# Generated deterministically by seda-macro-lef-normalizer-v1; recipe orfs-asap7-fakeram-m4-v1.
VERSION 5.8 ;
BUSBITCHARS "[]" ;
DIVIDERCHAR "/" ;

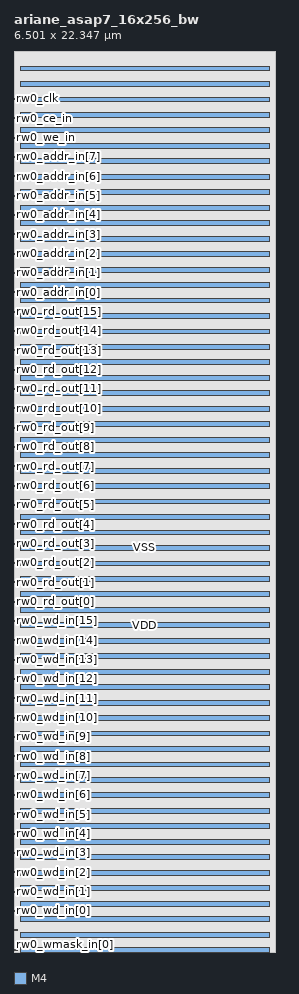
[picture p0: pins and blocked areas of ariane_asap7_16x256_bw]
MACRO ariane_asap7_16x256_bw
  FOREIGN ariane_asap7_16x256_bw 0 0 ;
  CLASS BLOCK ;
  ORIGIN 0 0 ;
  SIZE 6.501 BY 22.347 ;
  SYMMETRY X Y R90 ;
  PIN rw0_wmask_in[0]
    DIRECTION INPUT ;
    USE SIGNAL ;
    SHAPE ABUTMENT ;
    PORT
      LAYER M4 ;
      RECT 0.000 0.048 0.084 0.072 ;
    END
  END rw0_wmask_in[0]
  PIN rw0_wmask_in[1]
    DIRECTION INPUT ;
    USE SIGNAL ;
    SHAPE ABUTMENT ;
    PORT
      LAYER M4 ;
      RECT 0.000 0.528 0.084 0.552 ;
    END
  END rw0_wmask_in[1]
  PIN rw0_wd_in[0]
    DIRECTION INPUT ;
    USE SIGNAL ;
    SHAPE ABUTMENT ;
    PORT
      LAYER M4 ;
      RECT 0.000 1.008 0.084 1.032 ;
    END
  END rw0_wd_in[0]
  PIN rw0_wd_in[1]
    DIRECTION INPUT ;
    USE SIGNAL ;
    SHAPE ABUTMENT ;
    PORT
      LAYER M4 ;
      RECT 0.000 1.488 0.084 1.512 ;
    END
  END rw0_wd_in[1]
  PIN rw0_wd_in[2]
    DIRECTION INPUT ;
    USE SIGNAL ;
    SHAPE ABUTMENT ;
    PORT
      LAYER M4 ;
      RECT 0.000 1.968 0.084 1.992 ;
    END
  END rw0_wd_in[2]
  PIN rw0_wd_in[3]
    DIRECTION INPUT ;
    USE SIGNAL ;
    SHAPE ABUTMENT ;
    PORT
      LAYER M4 ;
      RECT 0.000 2.448 0.084 2.472 ;
    END
  END rw0_wd_in[3]
  PIN rw0_wd_in[4]
    DIRECTION INPUT ;
    USE SIGNAL ;
    SHAPE ABUTMENT ;
    PORT
      LAYER M4 ;
      RECT 0.000 2.928 0.084 2.952 ;
    END
  END rw0_wd_in[4]
  PIN rw0_wd_in[5]
    DIRECTION INPUT ;
    USE SIGNAL ;
    SHAPE ABUTMENT ;
    PORT
      LAYER M4 ;
      RECT 0.000 3.408 0.084 3.432 ;
    END
  END rw0_wd_in[5]
  PIN rw0_wd_in[6]
    DIRECTION INPUT ;
    USE SIGNAL ;
    SHAPE ABUTMENT ;
    PORT
      LAYER M4 ;
      RECT 0.000 3.888 0.084 3.912 ;
    END
  END rw0_wd_in[6]
  PIN rw0_wd_in[7]
    DIRECTION INPUT ;
    USE SIGNAL ;
    SHAPE ABUTMENT ;
    PORT
      LAYER M4 ;
      RECT 0.000 4.368 0.084 4.392 ;
    END
  END rw0_wd_in[7]
  PIN rw0_wd_in[8]
    DIRECTION INPUT ;
    USE SIGNAL ;
    SHAPE ABUTMENT ;
    PORT
      LAYER M4 ;
      RECT 0.000 4.848 0.084 4.872 ;
    END
  END rw0_wd_in[8]
  PIN rw0_wd_in[9]
    DIRECTION INPUT ;
    USE SIGNAL ;
    SHAPE ABUTMENT ;
    PORT
      LAYER M4 ;
      RECT 0.000 5.328 0.084 5.352 ;
    END
  END rw0_wd_in[9]
  PIN rw0_wd_in[10]
    DIRECTION INPUT ;
    USE SIGNAL ;
    SHAPE ABUTMENT ;
    PORT
      LAYER M4 ;
      RECT 0.000 5.808 0.084 5.832 ;
    END
  END rw0_wd_in[10]
  PIN rw0_wd_in[11]
    DIRECTION INPUT ;
    USE SIGNAL ;
    SHAPE ABUTMENT ;
    PORT
      LAYER M4 ;
      RECT 0.000 6.288 0.084 6.312 ;
    END
  END rw0_wd_in[11]
  PIN rw0_wd_in[12]
    DIRECTION INPUT ;
    USE SIGNAL ;
    SHAPE ABUTMENT ;
    PORT
      LAYER M4 ;
      RECT 0.000 6.768 0.084 6.792 ;
    END
  END rw0_wd_in[12]
  PIN rw0_wd_in[13]
    DIRECTION INPUT ;
    USE SIGNAL ;
    SHAPE ABUTMENT ;
    PORT
      LAYER M4 ;
      RECT 0.000 7.248 0.084 7.272 ;
    END
  END rw0_wd_in[13]
  PIN rw0_wd_in[14]
    DIRECTION INPUT ;
    USE SIGNAL ;
    SHAPE ABUTMENT ;
    PORT
      LAYER M4 ;
      RECT 0.000 7.728 0.084 7.752 ;
    END
  END rw0_wd_in[14]
  PIN rw0_wd_in[15]
    DIRECTION INPUT ;
    USE SIGNAL ;
    SHAPE ABUTMENT ;
    PORT
      LAYER M4 ;
      RECT 0.000 8.208 0.084 8.232 ;
    END
  END rw0_wd_in[15]
  PIN rw0_rd_out[0]
    DIRECTION OUTPUT ;
    USE SIGNAL ;
    SHAPE ABUTMENT ;
    PORT
      LAYER M4 ;
      RECT 0.000 8.688 0.084 8.712 ;
    END
  END rw0_rd_out[0]
  PIN rw0_rd_out[1]
    DIRECTION OUTPUT ;
    USE SIGNAL ;
    SHAPE ABUTMENT ;
    PORT
      LAYER M4 ;
      RECT 0.000 9.168 0.084 9.192 ;
    END
  END rw0_rd_out[1]
  PIN rw0_rd_out[2]
    DIRECTION OUTPUT ;
    USE SIGNAL ;
    SHAPE ABUTMENT ;
    PORT
      LAYER M4 ;
      RECT 0.000 9.648 0.084 9.672 ;
    END
  END rw0_rd_out[2]
  PIN rw0_rd_out[3]
    DIRECTION OUTPUT ;
    USE SIGNAL ;
    SHAPE ABUTMENT ;
    PORT
      LAYER M4 ;
      RECT 0.000 10.128 0.084 10.152 ;
    END
  END rw0_rd_out[3]
  PIN rw0_rd_out[4]
    DIRECTION OUTPUT ;
    USE SIGNAL ;
    SHAPE ABUTMENT ;
    PORT
      LAYER M4 ;
      RECT 0.000 10.608 0.084 10.632 ;
    END
  END rw0_rd_out[4]
  PIN rw0_rd_out[5]
    DIRECTION OUTPUT ;
    USE SIGNAL ;
    SHAPE ABUTMENT ;
    PORT
      LAYER M4 ;
      RECT 0.000 11.088 0.084 11.112 ;
    END
  END rw0_rd_out[5]
  PIN rw0_rd_out[6]
    DIRECTION OUTPUT ;
    USE SIGNAL ;
    SHAPE ABUTMENT ;
    PORT
      LAYER M4 ;
      RECT 0.000 11.568 0.084 11.592 ;
    END
  END rw0_rd_out[6]
  PIN rw0_rd_out[7]
    DIRECTION OUTPUT ;
    USE SIGNAL ;
    SHAPE ABUTMENT ;
    PORT
      LAYER M4 ;
      RECT 0.000 12.048 0.084 12.072 ;
    END
  END rw0_rd_out[7]
  PIN rw0_rd_out[8]
    DIRECTION OUTPUT ;
    USE SIGNAL ;
    SHAPE ABUTMENT ;
    PORT
      LAYER M4 ;
      RECT 0.000 12.528 0.084 12.552 ;
    END
  END rw0_rd_out[8]
  PIN rw0_rd_out[9]
    DIRECTION OUTPUT ;
    USE SIGNAL ;
    SHAPE ABUTMENT ;
    PORT
      LAYER M4 ;
      RECT 0.000 13.008 0.084 13.032 ;
    END
  END rw0_rd_out[9]
  PIN rw0_rd_out[10]
    DIRECTION OUTPUT ;
    USE SIGNAL ;
    SHAPE ABUTMENT ;
    PORT
      LAYER M4 ;
      RECT 0.000 13.488 0.084 13.512 ;
    END
  END rw0_rd_out[10]
  PIN rw0_rd_out[11]
    DIRECTION OUTPUT ;
    USE SIGNAL ;
    SHAPE ABUTMENT ;
    PORT
      LAYER M4 ;
      RECT 0.000 13.968 0.084 13.992 ;
    END
  END rw0_rd_out[11]
  PIN rw0_rd_out[12]
    DIRECTION OUTPUT ;
    USE SIGNAL ;
    SHAPE ABUTMENT ;
    PORT
      LAYER M4 ;
      RECT 0.000 14.448 0.084 14.472 ;
    END
  END rw0_rd_out[12]
  PIN rw0_rd_out[13]
    DIRECTION OUTPUT ;
    USE SIGNAL ;
    SHAPE ABUTMENT ;
    PORT
      LAYER M4 ;
      RECT 0.000 14.928 0.084 14.952 ;
    END
  END rw0_rd_out[13]
  PIN rw0_rd_out[14]
    DIRECTION OUTPUT ;
    USE SIGNAL ;
    SHAPE ABUTMENT ;
    PORT
      LAYER M4 ;
      RECT 0.000 15.408 0.084 15.432 ;
    END
  END rw0_rd_out[14]
  PIN rw0_rd_out[15]
    DIRECTION OUTPUT ;
    USE SIGNAL ;
    SHAPE ABUTMENT ;
    PORT
      LAYER M4 ;
      RECT 0.000 15.888 0.084 15.912 ;
    END
  END rw0_rd_out[15]
  PIN rw0_addr_in[0]
    DIRECTION INPUT ;
    USE SIGNAL ;
    SHAPE ABUTMENT ;
    PORT
      LAYER M4 ;
      RECT 0.000 16.368 0.084 16.392 ;
    END
  END rw0_addr_in[0]
  PIN rw0_addr_in[1]
    DIRECTION INPUT ;
    USE SIGNAL ;
    SHAPE ABUTMENT ;
    PORT
      LAYER M4 ;
      RECT 0.000 16.848 0.084 16.872 ;
    END
  END rw0_addr_in[1]
  PIN rw0_addr_in[2]
    DIRECTION INPUT ;
    USE SIGNAL ;
    SHAPE ABUTMENT ;
    PORT
      LAYER M4 ;
      RECT 0.000 17.328 0.084 17.352 ;
    END
  END rw0_addr_in[2]
  PIN rw0_addr_in[3]
    DIRECTION INPUT ;
    USE SIGNAL ;
    SHAPE ABUTMENT ;
    PORT
      LAYER M4 ;
      RECT 0.000 17.808 0.084 17.832 ;
    END
  END rw0_addr_in[3]
  PIN rw0_addr_in[4]
    DIRECTION INPUT ;
    USE SIGNAL ;
    SHAPE ABUTMENT ;
    PORT
      LAYER M4 ;
      RECT 0.000 18.288 0.084 18.312 ;
    END
  END rw0_addr_in[4]
  PIN rw0_addr_in[5]
    DIRECTION INPUT ;
    USE SIGNAL ;
    SHAPE ABUTMENT ;
    PORT
      LAYER M4 ;
      RECT 0.000 18.768 0.084 18.792 ;
    END
  END rw0_addr_in[5]
  PIN rw0_addr_in[6]
    DIRECTION INPUT ;
    USE SIGNAL ;
    SHAPE ABUTMENT ;
    PORT
      LAYER M4 ;
      RECT 0.000 19.248 0.084 19.272 ;
    END
  END rw0_addr_in[6]
  PIN rw0_addr_in[7]
    DIRECTION INPUT ;
    USE SIGNAL ;
    SHAPE ABUTMENT ;
    PORT
      LAYER M4 ;
      RECT 0.000 19.728 0.084 19.752 ;
    END
  END rw0_addr_in[7]
  PIN rw0_we_in
    DIRECTION INPUT ;
    USE SIGNAL ;
    SHAPE ABUTMENT ;
    PORT
      LAYER M4 ;
      RECT 0.000 20.208 0.084 20.232 ;
    END
  END rw0_we_in
  PIN rw0_ce_in
    DIRECTION INPUT ;
    USE SIGNAL ;
    SHAPE ABUTMENT ;
    PORT
      LAYER M4 ;
      RECT 0.000 20.688 0.084 20.712 ;
    END
  END rw0_ce_in
  PIN rw0_clk
    DIRECTION INPUT ;
    USE SIGNAL ;
    SHAPE ABUTMENT ;
    PORT
      LAYER M4 ;
      RECT 0.000 21.168 0.084 21.192 ;
    END
  END rw0_clk
  PIN VSS
    DIRECTION INOUT ;
    USE GROUND ;
    PORT
      LAYER M4 ;
      RECT 0.156 0.000 6.345 0.120 ;
      RECT 0.156 0.756 6.345 0.876 ;
      RECT 0.156 1.524 6.345 1.644 ;
      RECT 0.156 2.292 6.345 2.412 ;
      RECT 0.156 3.060 6.345 3.180 ;
      RECT 0.156 3.828 6.345 3.948 ;
      RECT 0.156 4.596 6.345 4.716 ;
      RECT 0.156 5.364 6.345 5.484 ;
      RECT 0.156 6.132 6.345 6.252 ;
      RECT 0.156 6.900 6.345 7.020 ;
      RECT 0.156 7.668 6.345 7.788 ;
      RECT 0.156 8.436 6.345 8.556 ;
      RECT 0.156 9.204 6.345 9.324 ;
      RECT 0.156 9.972 6.345 10.092 ;
      RECT 0.156 10.740 6.345 10.860 ;
      RECT 0.156 11.508 6.345 11.628 ;
      RECT 0.156 12.276 6.345 12.396 ;
      RECT 0.156 13.044 6.345 13.164 ;
      RECT 0.156 13.812 6.345 13.932 ;
      RECT 0.156 14.580 6.345 14.700 ;
      RECT 0.156 15.348 6.345 15.468 ;
      RECT 0.156 16.116 6.345 16.236 ;
      RECT 0.156 16.884 6.345 17.004 ;
      RECT 0.156 17.652 6.345 17.772 ;
      RECT 0.156 18.420 6.345 18.540 ;
      RECT 0.156 19.188 6.345 19.308 ;
      RECT 0.156 19.956 6.345 20.076 ;
      RECT 0.156 20.724 6.345 20.844 ;
      RECT 0.156 21.492 6.345 21.612 ;
    END
  END VSS
  PIN VDD
    DIRECTION INOUT ;
    USE POWER ;
    PORT
      LAYER M4 ;
      RECT 0.156 0.372 6.345 0.492 ;
      RECT 0.156 1.140 6.345 1.260 ;
      RECT 0.156 1.908 6.345 2.028 ;
      RECT 0.156 2.676 6.345 2.796 ;
      RECT 0.156 3.444 6.345 3.564 ;
      RECT 0.156 4.212 6.345 4.332 ;
      RECT 0.156 4.980 6.345 5.100 ;
      RECT 0.156 5.748 6.345 5.868 ;
      RECT 0.156 6.516 6.345 6.636 ;
      RECT 0.156 7.284 6.345 7.404 ;
      RECT 0.156 8.052 6.345 8.172 ;
      RECT 0.156 8.820 6.345 8.940 ;
      RECT 0.156 9.588 6.345 9.708 ;
      RECT 0.156 10.356 6.345 10.476 ;
      RECT 0.156 11.124 6.345 11.244 ;
      RECT 0.156 11.892 6.345 12.012 ;
      RECT 0.156 12.660 6.345 12.780 ;
      RECT 0.156 13.428 6.345 13.548 ;
      RECT 0.156 14.196 6.345 14.316 ;
      RECT 0.156 14.964 6.345 15.084 ;
      RECT 0.156 15.732 6.345 15.852 ;
      RECT 0.156 16.500 6.345 16.620 ;
      RECT 0.156 17.268 6.345 17.388 ;
      RECT 0.156 18.036 6.345 18.156 ;
      RECT 0.156 18.804 6.345 18.924 ;
      RECT 0.156 19.572 6.345 19.692 ;
      RECT 0.156 20.340 6.345 20.460 ;
      RECT 0.156 21.108 6.345 21.228 ;
      RECT 0.156 21.876 6.345 21.996 ;
    END
  END VDD
  OBS
    LAYER M1 ;
    RECT 0 0 6.501 22.347 ;
    LAYER M2 ;
    RECT 0 0 6.501 22.347 ;
    LAYER M3 ;
    RECT 0 0 6.501 22.347 ;
  END
END ariane_asap7_16x256_bw

END LIBRARY
